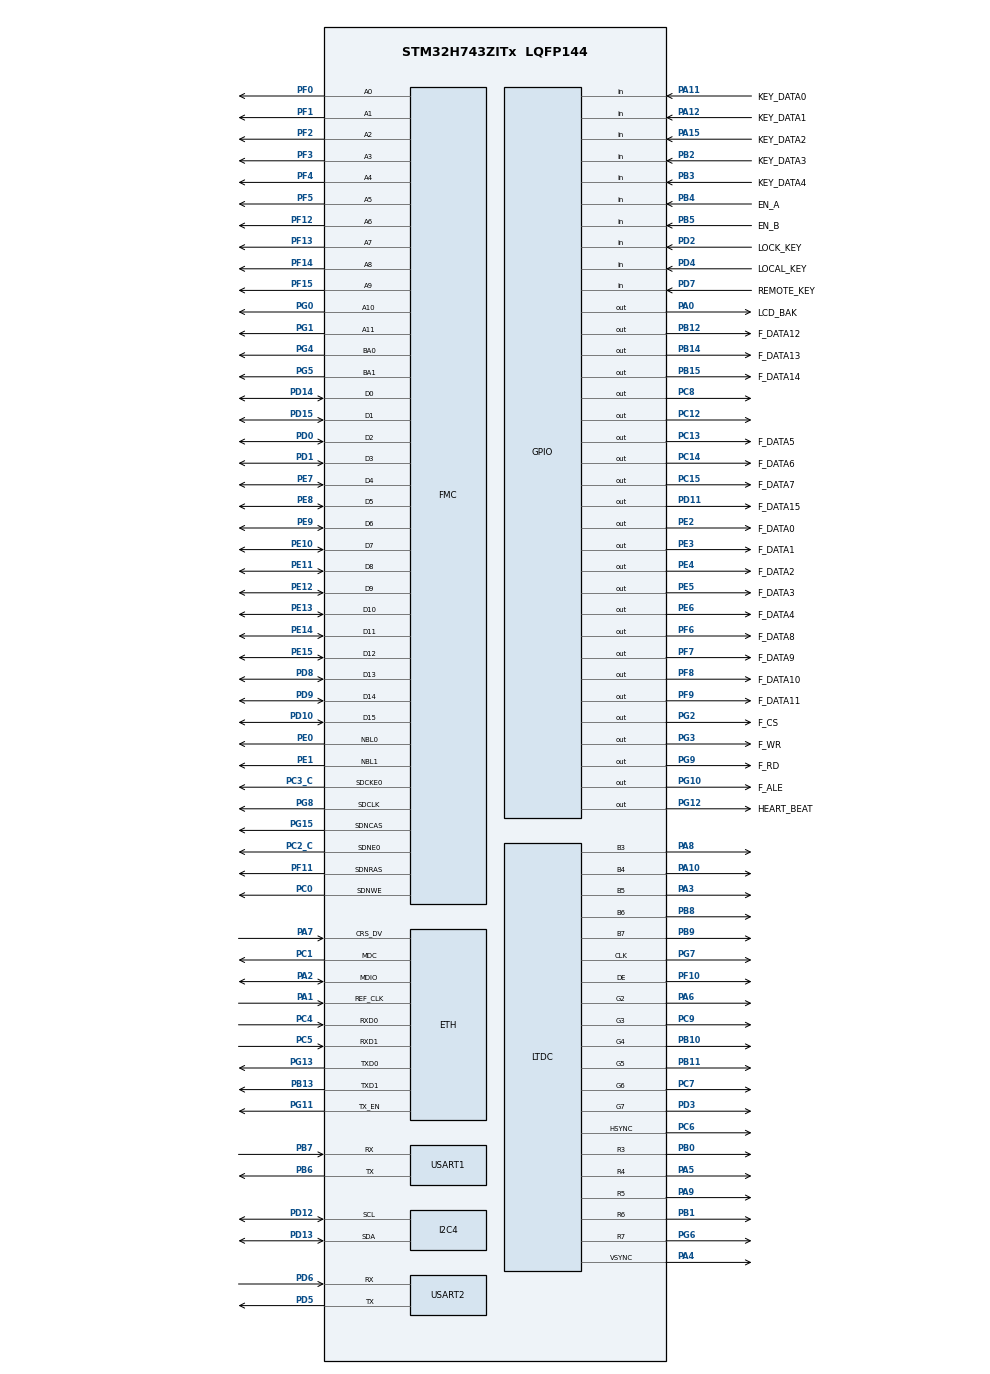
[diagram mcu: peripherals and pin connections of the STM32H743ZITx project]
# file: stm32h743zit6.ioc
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CORTEX_M7.AccessPermission_S-Cortex_Memory_Protection_Unit_Region1_Settings_S=MPU_REGION_FULL_ACCESS
CORTEX_M7.AccessPermission_S-Cortex_Memory_Protection_Unit_Region2_Settings_S=MPU_REGION_FULL_ACCESS
CORTEX_M7.AccessPermission_S-Cortex_Memory_Protection_Unit_Region3_Settings_S=MPU_REGION_FULL_ACCESS
CORTEX_M7.BaseAddress_S-Cortex_Memory_Protection_Unit_Region1_Settings_S=0x30020000
CORTEX_M7.BaseAddress_S-Cortex_Memory_Protection_Unit_Region2_Settings_S=0x30040000
CORTEX_M7.BaseAddress_S-Cortex_Memory_Protection_Unit_Region3_Settings_S=0xC0000000
CORTEX_M7.CPU_DCache=Enabled
CORTEX_M7.CPU_ICache=Enabled
CORTEX_M7.DisableExec_S-Cortex_Memory_Protection_Unit_Region1_Settings_S=MPU_INSTRUCTION_ACCESS_DISABLE
CORTEX_M7.DisableExec_S-Cortex_Memory_Protection_Unit_Region2_Settings_S=MPU_INSTRUCTION_ACCESS_DISABLE
CORTEX_M7.DisableExec_S-Cortex_Memory_Protection_Unit_Region3_Settings_S=MPU_INSTRUCTION_ACCESS_DISABLE
CORTEX_M7.Enable_S-Cortex_Memory_Protection_Unit_Region1_Settings_S=MPU_REGION_ENABLE
CORTEX_M7.Enable_S-Cortex_Memory_Protection_Unit_Region2_Settings_S=MPU_REGION_ENABLE
CORTEX_M7.Enable_S-Cortex_Memory_Protection_Unit_Region3_Settings_S=MPU_REGION_ENABLE
CORTEX_M7.Enable_S-Cortex_Memory_Protection_Unit_Region4_Settings_S=__NULL
CORTEX_M7.Enable_S-Cortex_Memory_Protection_Unit_Region5_Settings_S=__NULL
CORTEX_M7.IsBufferable_S-Cortex_Memory_Protection_Unit_Region2_Settings_S=MPU_ACCESS_BUFFERABLE
CORTEX_M7.IsBufferable_S-Cortex_Memory_Protection_Unit_Region3_Settings_S=MPU_ACCESS_NOT_BUFFERABLE
CORTEX_M7.IsCacheable_S-Cortex_Memory_Protection_Unit_Region3_Settings_S=MPU_ACCESS_NOT_CACHEABLE
CORTEX_M7.IsShareable_S-Cortex_Memory_Protection_Unit_Region2_Settings_S=MPU_ACCESS_SHAREABLE
CORTEX_M7.IsShareable_S-Cortex_Memory_Protection_Unit_Region3_Settings_S=MPU_ACCESS_NOT_SHAREABLE
CORTEX_M7.MPU_Control=MPU_PRIVILEGED_DEFAULT
CORTEX_M7.Size_S-Cortex_Memory_Protection_Unit_Region1_Settings_S=MPU_REGION_SIZE_128KB
CORTEX_M7.Size_S-Cortex_Memory_Protection_Unit_Region2_Settings_S=MPU_REGION_SIZE_512B
CORTEX_M7.Size_S-Cortex_Memory_Protection_Unit_Region3_Settings_S=MPU_REGION_SIZE_8MB
CORTEX_M7.TypeExtField_S-Cortex_Memory_Protection_Unit_Region1_Settings_S=MPU_TEX_LEVEL1
CORTEX_M7.default_mode_Activation=1
DMA2D.ColorMode=DMA2D_OUTPUT_RGB565
ETH.ETH_RX_DESC_CNT=4
ETH.ETH_TX_DESC_CNT=4
ETH.MediaInterface=HAL_ETH_RMII_MODE
ETH.RxDescAddress=0x30040000
ETH.TxDescAddress=0x30040200
FMC.CASLatency1=FMC_SDRAM_CAS_LATENCY_2
FMC.ColumnBitsNumber1=FMC_SDRAM_COLUMN_BITS_NUM_8
FMC.ExitSelfRefreshDelay1=7
FMC.LoadToActiveDelay1=2
FMC.RCDDelay1=2
FMC.RPDelay1=2
FMC.ReadBurst1=FMC_SDRAM_RBURST_ENABLE
FMC.ReadPipeDelay1=FMC_SDRAM_RPIPE_DELAY_1
FMC.ReadPipeDelay2=FMC_SDRAM_RPIPE_DELAY_1
FMC.RowCycleDelay1=7
FMC.RowCycleDelay2=7
FMC.SDClockPeriod1=FMC_SDRAM_CLOCK_PERIOD_2
FMC.SelfRefreshTime1=4
FMC.WriteRecoveryTime1=3
FREERTOS.Tasks01=MainTask,0,256,StartDefaultTask,Default,NULL,Dynamic,NULL,NULL
I2C4.Timing=0x307075B1
LTDC.ActiveH=272
LTDC.ActiveW=480
LTDC.Alpha0_L0=255
LTDC.Alpha0_L1=255
LTDC.Alpha_L0=255
LTDC.Alpha_L1=255
LTDC.DEPolarity=LTDC_DEPOLARITY_AH
LTDC.FBStartAdress_L0=0xC0000000
LTDC.FBStartAdress_L1=0xC0000000
LTDC.HBP=43
LTDC.HFP=8
LTDC.HSync=4
LTDC.ImageHeight_L0=272
LTDC.ImageHeight_L1=272
LTDC.ImageWidth_L0=480
LTDC.Layers=0
LTDC.PCPolarity=LTDC_PCPOLARITY_IIPC
LTDC.PixelFormat_L0=LTDC_PIXEL_FORMAT_RGB565
LTDC.VBP=12
LTDC.VFP=8
LTDC.VSync=4
LTDC.WindowX1_L0=480
LTDC.WindowX1_L1=480
LTDC.WindowY1_L0=272
LTDC.WindowY1_L1=272
LWIP.BSP.number=1
LWIP.CHECKSUM_CHECK_ICMP=1
LWIP.CHECKSUM_GEN_ICMP=1
LWIP.DEFAULT_THREAD_STACKSIZE=2048
LWIP.ETH_RX_BUFFER_CNT=12
LWIP.GATEWAY_ADDRESS=192.168.000.000
LWIP.IP_ADDRESS=192.168.000.050
LWIP.LWIP_DHCP=0
LWIP.LWIP_RAM_HEAP_POINTER=0x30020000
LWIP.MEM_SIZE=131048
LWIP.NETMASK_ADDRESS=255.255.255.000
LWIP.SYS_LIGHTWEIGHT_PROT=1
LWIP.TCPIP_THREAD_STACKSIZE=2048
LWIP.TCP_MSS=1460
LWIP.TCP_QUEUE_OOSEQ=1
LWIP.TCP_SND_BUF=5840
LWIP.TCP_SND_QUEUELEN=16
LWIP.TCP_WND=5840
LWIP.Version=v2.1.2_Cube
LWIP0.BSP.STBoard=false
LWIP0.BSP.api=BSP_COMPONENT_DRIVER
LWIP0.BSP.component=LAN8742
LWIP0.BSP.instance=LAN8742
LWIP0.BSP.name=Driver_PHY
LWIP0.BSP.semaphore=S_LAN8742
LWIP0.BSP.solution=LAN8742
Mcu.Family=STM32H7
Mcu.Name=STM32H743ZITx
Mcu.Package=LQFP144
NVIC.ETH_IRQn=true\:5\:0\:false\:false\:true\:true\:true\:true\:true
NVIC.LTDC_ER_IRQn=true\:5\:0\:false\:false\:true\:true\:true\:true\:true
NVIC.LTDC_IRQn=true\:5\:0\:false\:false\:true\:true\:true\:true\:true
NVIC.PriorityGroup=NVIC_PRIORITYGROUP_4
NVIC.TIM1_UP_IRQn=true\:15\:0\:false\:false\:true\:false\:false\:true\:true
NVIC.TimeBase=TIM1_UP_IRQn
NVIC.TimeBaseIP=TIM1
PA0.GPIO_Label=LCD_BAK
PA0.Signal=GPIO_Output
PA1.GPIO_Speed=GPIO_SPEED_FREQ_VERY_HIGH
PA1.Mode=RMII
PA1.Signal=ETH_REF_CLK
PA10.GPIO_Speed=GPIO_SPEED_FREQ_VERY_HIGH
PA10.Mode=RGB565
PA10.Signal=LTDC_B4
PA11.GPIO_Label=KEY_DATA0
PA11.Signal=GPIO_Input
PA12.GPIO_Label=KEY_DATA1
PA12.Signal=GPIO_Input
PA13\ (JTMS/SWDIO).Mode=Serial_Wire
PA13\ (JTMS/SWDIO).Signal=DEBUG_JTMS-SWDIO
PA14\ (JTCK/SWCLK).Mode=Serial_Wire
PA14\ (JTCK/SWCLK).Signal=DEBUG_JTCK-SWCLK
PA15\ (JTDI).GPIO_Label=KEY_DATA2
PA15\ (JTDI).Signal=GPIO_Input
PA2.GPIO_Speed=GPIO_SPEED_FREQ_VERY_HIGH
PA2.Mode=RMII
PA2.Signal=ETH_MDIO
PA3.GPIO_Speed=GPIO_SPEED_FREQ_VERY_HIGH
PA3.Mode=RGB565
PA3.Signal=LTDC_B5
PA4.GPIO_Speed=GPIO_SPEED_FREQ_VERY_HIGH
PA4.Mode=RGB565
PA4.Signal=LTDC_VSYNC
PA5.GPIO_Speed=GPIO_SPEED_FREQ_VERY_HIGH
PA5.Mode=RGB565
PA5.Signal=LTDC_R4
PA6.GPIO_Speed=GPIO_SPEED_FREQ_VERY_HIGH
PA6.Mode=RGB565
PA6.Signal=LTDC_G2
PA7.GPIO_Speed=GPIO_SPEED_FREQ_VERY_HIGH
PA7.Mode=RMII
PA7.Signal=ETH_CRS_DV
PA8.GPIO_Speed=GPIO_SPEED_FREQ_VERY_HIGH
PA8.Mode=RGB565
PA8.Signal=LTDC_B3
PA9.GPIO_Speed=GPIO_SPEED_FREQ_VERY_HIGH
PA9.Mode=RGB565
PA9.Signal=LTDC_R5
PB0.GPIO_Speed=GPIO_SPEED_FREQ_VERY_HIGH
PB0.Mode=RGB565
PB0.Signal=LTDC_R3
PB1.GPIO_Speed=GPIO_SPEED_FREQ_VERY_HIGH
PB1.Mode=RGB565
PB1.Signal=LTDC_R6
PB10.GPIO_Speed=GPIO_SPEED_FREQ_VERY_HIGH
PB10.Mode=RGB565
PB10.Signal=LTDC_G4
PB11.GPIO_Speed=GPIO_SPEED_FREQ_VERY_HIGH
PB11.Mode=RGB565
PB11.Signal=LTDC_G5
PB12.GPIO_Label=F_DATA12
PB12.Signal=GPIO_Output
PB13.GPIO_Speed=GPIO_SPEED_FREQ_VERY_HIGH
PB13.Mode=RMII
PB13.Signal=ETH_TXD1
PB14.GPIO_Label=F_DATA13
PB14.Signal=GPIO_Output
PB15.GPIO_Label=F_DATA14
PB15.Signal=GPIO_Output
PB2.GPIO_Label=KEY_DATA3
PB2.Signal=GPIO_Input
PB3\ (JTDO/TRACESWO).GPIO_Label=KEY_DATA4
PB3\ (JTDO/TRACESWO).Signal=GPIO_Input
PB4\ (NJTRST).GPIO_Label=EN_A
PB4\ (NJTRST).Signal=GPIO_Input
PB5.GPIO_Label=EN_B
PB5.Signal=GPIO_Input
PB6.Mode=Asynchronous
PB6.Signal=USART1_TX
PB7.Mode=Asynchronous
PB7.Signal=USART1_RX
PB8.GPIO_FM8=SYSCFG_PMCR_I2C_PB8_FMP
PB8.GPIO_Speed=GPIO_SPEED_FREQ_VERY_HIGH
PB8.Mode=RGB565
PB8.Signal=LTDC_B6
PB9.GPIO_FM9=SYSCFG_PMCR_I2C_PB9_FMP
PB9.GPIO_Speed=GPIO_SPEED_FREQ_VERY_HIGH
PB9.Mode=RGB565
PB9.Signal=LTDC_B7
PC0.Signal=FMC_SDNWE
PC1.GPIO_Speed=GPIO_SPEED_FREQ_VERY_HIGH
PC1.Mode=RMII
PC1.Signal=ETH_MDC
PC12.Signal=GPIO_Output
PC13.GPIO_Label=F_DATA5
PC13.Signal=GPIO_Output
PC14-OSC32_IN\ (OSC32_IN).GPIO_Label=F_DATA6
PC14-OSC32_IN\ (OSC32_IN).Signal=GPIO_Output
PC15-OSC32_OUT\ (OSC32_OUT).GPIO_Label=F_DATA7
PC15-OSC32_OUT\ (OSC32_OUT).Signal=GPIO_Output
PC2_C.Mode=SdramChipSelect1_1
PC2_C.Signal=FMC_SDNE0
PC3_C.Mode=SdramChipSelect1_1
PC3_C.PinAttribute=Free
PC3_C.Signal=FMC_SDCKE0
PC4.GPIO_Speed=GPIO_SPEED_FREQ_VERY_HIGH
PC4.Mode=RMII
PC4.Signal=ETH_RXD0
PC5.GPIO_Speed=GPIO_SPEED_FREQ_VERY_HIGH
PC5.Mode=RMII
PC5.Signal=ETH_RXD1
PC6.GPIO_Speed=GPIO_SPEED_FREQ_VERY_HIGH
PC6.Mode=RGB565
PC6.Signal=LTDC_HSYNC
PC7.GPIO_Speed=GPIO_SPEED_FREQ_VERY_HIGH
PC7.Mode=RGB565
PC7.Signal=LTDC_G6
PC8.Signal=GPIO_Output
PC9.GPIO_Speed=GPIO_SPEED_FREQ_VERY_HIGH
PC9.Mode=RGB565
PC9.Signal=LTDC_G3
PD0.Signal=FMC_D2_DA2
PD1.Signal=FMC_D3_DA3
PD10.Signal=FMC_D15_DA15
PD11.GPIO_Label=F_DATA15
PD11.Signal=GPIO_Output
PD12.Mode=I2C
PD12.Signal=I2C4_SCL
PD13.Mode=I2C
PD13.Signal=I2C4_SDA
PD14.Signal=FMC_D0_DA0
PD15.Signal=FMC_D1_DA1
PD2.GPIO_Label=LOCK_KEY
PD2.Signal=GPIO_Input
PD3.GPIO_Speed=GPIO_SPEED_FREQ_VERY_HIGH
PD3.Mode=RGB565
PD3.Signal=LTDC_G7
PD4.GPIO_Label=LOCAL_KEY
PD4.Signal=GPIO_Input
PD5.Mode=Asynchronous
PD5.Signal=USART2_TX
PD6.Mode=Asynchronous
PD6.Signal=USART2_RX
PD7.GPIO_Label=REMOTE_KEY
PD7.Signal=GPIO_Input
PD8.Signal=FMC_D13_DA13
PD9.Signal=FMC_D14_DA14
PE0.Signal=FMC_NBL0
PE1.Signal=FMC_NBL1
PE10.Signal=FMC_D7_DA7
PE11.Signal=FMC_D8_DA8
PE12.Signal=FMC_D9_DA9
PE13.Signal=FMC_D10_DA10
PE14.Signal=FMC_D11_DA11
PE15.Signal=FMC_D12_DA12
PE2.GPIO_Label=F_DATA0
PE2.Signal=GPIO_Output
PE3.GPIO_Label=F_DATA1
PE3.Signal=GPIO_Output
PE4.GPIO_Label=F_DATA2
PE4.Signal=GPIO_Output
PE5.GPIO_Label=F_DATA3
PE5.Signal=GPIO_Output
PE6.GPIO_Label=F_DATA4
PE6.Signal=GPIO_Output
PE7.Signal=FMC_D4_DA4
PE8.Signal=FMC_D5_DA5
PE9.Signal=FMC_D6_DA6
PF0.Signal=FMC_A0
PF1.Signal=FMC_A1
PF10.GPIO_Speed=GPIO_SPEED_FREQ_VERY_HIGH
PF10.Mode=RGB565
PF10.Signal=LTDC_DE
PF11.Signal=FMC_SDNRAS
PF12.Signal=FMC_A6
PF13.Signal=FMC_A7
PF14.Signal=FMC_A8
PF15.Signal=FMC_A9
PF2.Signal=FMC_A2
PF3.Signal=FMC_A3
PF4.Signal=FMC_A4
PF5.Signal=FMC_A5
PF6.GPIO_Label=F_DATA8
PF6.Signal=GPIO_Output
PF7.GPIO_Label=F_DATA9
PF7.Signal=GPIO_Output
PF8.GPIO_Label=F_DATA10
PF8.Signal=GPIO_Output
PF9.GPIO_Label=F_DATA11
PF9.Signal=GPIO_Output
PG0.Signal=FMC_A10
PG1.Signal=FMC_A11
PG10.GPIO_Label=F_ALE
PG10.Signal=GPIO_Output
PG11.GPIO_Speed=GPIO_SPEED_FREQ_VERY_HIGH
PG11.Mode=RMII
PG11.Signal=ETH_TX_EN
PG12.GPIO_Label=HEART_BEAT
PG12.Signal=GPIO_Output
PG13.GPIO_Speed=GPIO_SPEED_FREQ_VERY_HIGH
PG13.Mode=RMII
PG13.Signal=ETH_TXD0
PG15.Signal=FMC_SDNCAS
PG2.GPIO_Label=F_CS
PG2.Signal=GPIO_Output
PG3.GPIO_Label=F_WR
PG3.Signal=GPIO_Output
PG4.Signal=FMC_A14_BA0
PG5.Signal=FMC_A15_BA1
PG6.GPIO_Speed=GPIO_SPEED_FREQ_VERY_HIGH
PG6.Mode=RGB565
PG6.Signal=LTDC_R7
PG7.GPIO_Speed=GPIO_SPEED_FREQ_VERY_HIGH
PG7.Mode=RGB565
PG7.Signal=LTDC_CLK
PG8.Signal=FMC_SDCLK
PG9.GPIO_Label=F_RD
PG9.Signal=GPIO_Output
PH0-OSC_IN\ (PH0).Mode=HSE-External-Oscillator
PH0-OSC_IN\ (PH0).Signal=RCC_OSC_IN
PH1-OSC_OUT\ (PH1).Mode=HSE-External-Oscillator
PH1-OSC_OUT\ (PH1).Signal=RCC_OSC_OUT
ProjectManager.HeapSize=0x200
ProjectManager.StackSize=0x400
ProjectManager.TargetToolchain=STM32CubeIDE
RCC.ADCFreq_Value=143750000
RCC.APB1Freq_Value=120000000
RCC.APB2Freq_Value=120000000
RCC.APB3Freq_Value=120000000
RCC.APB4Freq_Value=120000000
RCC.CortexFreq_Value=480000000
RCC.D1PPRE=RCC_APB3_DIV2
RCC.D2PPRE1=RCC_APB1_DIV2
RCC.D2PPRE2=RCC_APB2_DIV2
RCC.D3PPRE=RCC_APB4_DIV2
RCC.DIVM1=5
RCC.DIVM2=6
RCC.DIVM3=16
RCC.DIVN1=192
RCC.DIVN2=69
RCC.DIVN3=140
RCC.DIVQ2=4
RCC.DIVR3=36
RCC.FMCCLockSelection=RCC_FMCCLKSOURCE_PLL2
RCC.HCLKFreq_Value=240000000
RCC.HPRE=RCC_HCLK_DIV2
RCC.PLL2FRACN=0
RCC.PLL3FRACN=0
RCC.PLLFRACN=0
RCC.PLLSourceVirtual=RCC_PLLSOURCE_HSE
RCC.SYSCLKFreq_VALUE=480000000
RCC.SYSCLKSource=RCC_SYSCLKSOURCE_PLLCLK
RCC.USBFreq_Value=480000000
SH.FMC_A0.0=FMC_A0,12b-sda1
SH.FMC_A1.0=FMC_A1,12b-sda1
SH.FMC_A10.0=FMC_A10,12b-sda1
SH.FMC_A11.0=FMC_A11,12b-sda1
SH.FMC_A14_BA0.0=FMC_BA0,FourSdramBanks1
SH.FMC_A15_BA1.0=FMC_BA1,FourSdramBanks1
SH.FMC_A2.0=FMC_A2,12b-sda1
SH.FMC_A3.0=FMC_A3,12b-sda1
SH.FMC_A4.0=FMC_A4,12b-sda1
SH.FMC_A5.0=FMC_A5,12b-sda1
SH.FMC_A6.0=FMC_A6,12b-sda1
SH.FMC_A7.0=FMC_A7,12b-sda1
SH.FMC_A8.0=FMC_A8,12b-sda1
SH.FMC_A9.0=FMC_A9,12b-sda1
SH.FMC_D0_DA0.0=FMC_D0,sd-16b-d1
SH.FMC_D10_DA10.0=FMC_D10,sd-16b-d1
SH.FMC_D11_DA11.0=FMC_D11,sd-16b-d1
SH.FMC_D12_DA12.0=FMC_D12,sd-16b-d1
SH.FMC_D13_DA13.0=FMC_D13,sd-16b-d1
SH.FMC_D14_DA14.0=FMC_D14,sd-16b-d1
SH.FMC_D15_DA15.0=FMC_D15,sd-16b-d1
SH.FMC_D1_DA1.0=FMC_D1,sd-16b-d1
SH.FMC_D2_DA2.0=FMC_D2,sd-16b-d1
SH.FMC_D3_DA3.0=FMC_D3,sd-16b-d1
SH.FMC_D4_DA4.0=FMC_D4,sd-16b-d1
SH.FMC_D5_DA5.0=FMC_D5,sd-16b-d1
SH.FMC_D6_DA6.0=FMC_D6,sd-16b-d1
SH.FMC_D7_DA7.0=FMC_D7,sd-16b-d1
SH.FMC_D8_DA8.0=FMC_D8,sd-16b-d1
SH.FMC_D9_DA9.0=FMC_D9,sd-16b-d1
SH.FMC_NBL0.0=FMC_NBL0,Sd2ByteEnable1
SH.FMC_NBL1.0=FMC_NBL1,Sd2ByteEnable1
SH.FMC_SDCLK.0=FMC_SDCLK,12b-sda1
SH.FMC_SDNCAS.0=FMC_SDNCAS,12b-sda1
SH.FMC_SDNRAS.0=FMC_SDNRAS,12b-sda1
SH.FMC_SDNWE.0=FMC_SDNWE,12b-sda1
USART1.VirtualMode-Asynchronous=VM_ASYNC
USART2.VirtualMode-Asynchronous=VM_ASYNC
VP_DMA2D_VS_DMA2D.Mode=DMA2D_Activate
VP_FREERTOS_VS_CMSIS_V1.Mode=CMSIS_V1
VP_LWIP_VS_Enabled.Mode=Enabled
VP_MEMORYMAP_VS_MEMORYMAP.Mode=CurAppReg
VP_SYS_VS_tim1.Mode=TIM1
board=custom

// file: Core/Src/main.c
/* USER CODE BEGIN Header */
/**
  ******************************************************************************
  * @file           : main.c
  * @brief          : Main program body
  ******************************************************************************
  * @attention
  *
  * Copyright (c) 2026 STMicroelectronics.
  * All rights reserved.
  *
  * This software is licensed under terms that can be found in the LICENSE file
  * in the root directory of this software component.
  * If no LICENSE file comes with this software, it is provided AS-IS.
  *
  ******************************************************************************
  */
/* USER CODE END Header */
#include "main.h"
#include "cmsis_os.h"
#include "lwip.h"

/* USER CODE BEGIN Includes */
#include <stdint.h>
#include <string.h>
#include <stdbool.h>
#include "stm32h743xx.h"
#include "stm32h7xx_hal_cortex.h"
#include "tcp_ip.h"
#include "lwip/tcp.h"
#include "lwip/pbuf.h"
#include "lcd.h"
#include "../Middlewares/lvgl/lvgl.h"
#include "lv_port_disp.h"
#include "lv_port_indev.h"
#include "com_define.h"
#include "sdram.h"
#include "widgets.h"
#include "hw.h"
#include <stdio.h>
#include <sys/types.h>
#include "user_def.h"
#include "ax_uart2.h"
#include "packet_task.h"
#include "ax_mcu_if.h"
#include "ax_eeprom.h"
#include "reg_addr.h"
#include "ax_eeprom_task.h"
#include "com_widget.h"
/* USER CODE END Includes */

/* USER CODE BEGIN PTD */
uint16_t *FrameBuffer = (uint16_t *)LCD_FB_ADDR;
extern struct netif gnetif;
/* USER CODE END PTD */

DMA2D_HandleTypeDef hdma2d;

I2C_HandleTypeDef hi2c4;

LTDC_HandleTypeDef hltdc;

UART_HandleTypeDef huart1;
UART_HandleTypeDef huart2;

SDRAM_HandleTypeDef hsdram1;

osThreadId MainTaskHandle;
/* USER CODE BEGIN PV */

static void MX_NVIC_Init(void);
void HAL_UART_RxCpltCallback(UART_HandleTypeDef *huart);
/* USER CODE END PV */

void SystemClock_Config(void);
static void MPU_Config(void);
static void MX_GPIO_Init(void);
static void MX_FMC_Init(void);
static void MX_I2C4_Init(void);
static void MX_USART1_UART_Init(void);
static void MX_USART2_UART_Init(void);
static void MX_DMA2D_Init(void);
static void MX_LTDC_Init(void);
void StartDefaultTask(void const * argument);

/* USER CODE BEGIN PFP */
uint8_t gete_way_ip[4] = {192,168,0,1};	//user set up
uint8_t user_ip[4] = {192,168,0,50};
uint16_t Port_No = 5001;
uint32_t g_rs232_baud = 115200;

volatile bool btcp_connect = false;

#define U2_RX_BUF_SZ 256  //uart 버퍼 크기
volatile uint8_t u2_rx_buf[U2_RX_BUF_SZ];
volatile uint16_t u2_rx_w = 0;
uint8_t rx2_data = 0;

uint8_t g_tcp_recv_buffer[TCP_RECV_BUF_SIZE];	//TCP로 데이터를 받는다...
volatile uint32_t g_tcp_recv_len = 0;
volatile bool g_tcp_new_data_flag = false;
/* USER CODE END PFP */

int main(void)
{

  /* MPU Configuration--------------------------------------------------------*/
  MPU_Config();

  /* Enable the CPU Cache */

  /* Enable I-Cache---------------------------------------------------------*/
  SCB_EnableICache();

  /* Enable D-Cache---------------------------------------------------------*/
  SCB_EnableDCache();

  /* MCU Configuration--------------------------------------------------------*/

  /* Reset of all peripherals, Initializes the Flash interface and the Systick. */
  HAL_Init();

  /* Configure the system clock */
  SystemClock_Config();

  /* Initialize all configured peripherals */
  MX_GPIO_Init();
  MX_FMC_Init();
  MX_I2C4_Init();
  MX_USART1_UART_Init();
  MX_USART2_UART_Init();
  MX_DMA2D_Init();
  MX_LTDC_Init();
  /* USER CODE BEGIN 2 */
  MX_NVIC_Init();

  //LAN8742 RESET PIN
  HAL_GPIO_WritePin(GPIOC, GPIO_PIN_10, GPIO_PIN_RESET);
  HAL_Delay(100);
  HAL_GPIO_WritePin(GPIOC, GPIO_PIN_10, GPIO_PIN_SET);
  HAL_Delay(500);

  HAL_GPIO_WritePin(GPIOC, GPIO_PIN_8, GPIO_PIN_SET);	//DISP Control
  HAL_Delay(250); // Datasheet: Wait T2 (250ms min) after DISP High before turning on Backlight
  HAL_GPIO_WritePin(GPIOA, LCD_BAK_Pin, GPIO_PIN_RESET);	//LCD Backlight off

  packet_init();
  HAL_Delay(1000);

  setvbuf(stdout, NULL, _IONBF, 0); // No buffering

  HAL_StatusTypeDef st = HAL_UART_Receive_IT(&huart2, &rx2_data, 1);
  if(st != HAL_OK) {
    uart2_puts("\r\nUSART2 Receive_IT failed\r\n");
  }

  printf("\r\n\r\n App Start 2025. 12. 10b \r\n");
  uart2_puts("\r\n\r\n [Debug] App Start 2025. 12. 10b \r\n");

//  HAL_UART_Receive_IT(&huart1, (uint8_t*) &rx1_data, 1);
//  HAL_UART_Receive_IT(&huart2, (uint8_t*) &rx2_data, 1);
  HAL_Delay(100);

  // -----------------------------------------------------------------------------
  // power on, eeprom 에서 데이터를 읽어옴.
  // g_oper_mode =  0; //트리거모드
  // g_oper_mode =  1; //시퀀스모드
  // default_value_init(); //기본 값
  // eeprom_save_sys();

//  eeprom_save_facotry();

  eeprom_load_sys();					// load sys data from eeprom
  load_user_param(g_user_default);		// load trig_mode param from eeprom
  eeprom_load_page_all();				// load sequence mode param from eeprom

  mcu_write16(rSTROBE_EN, 0xffff);		// fpga write, strobe_enable
  mcu_write16(rSTROBE_EN, 0xffff);
  uart2_puts_16h("\r\n rSTROBE_EN : 0x", mcu_read16(rSTROBE_EN));

  /* USER CODE END 2 */

  /* Create the thread(s) */
  /* definition and creation of MainTask */
  osThreadDef(MainTask, StartDefaultTask, osPriorityNormal, 0, 2048);
  MainTaskHandle = osThreadCreate(osThread(MainTask), NULL);

  /* Start scheduler */
  osKernelStart();

  /* We should never get here as control is now taken by the scheduler */

  /* Infinite loop */
  while (1)
  {

  }
}

void SystemClock_Config(void)
{
  RCC_OscInitTypeDef RCC_OscInitStruct = {0};
  RCC_ClkInitTypeDef RCC_ClkInitStruct = {0};

  /** Supply configuration update enable
  */
  HAL_PWREx_ConfigSupply(PWR_LDO_SUPPLY);

  /** Configure the main internal regulator output voltage
  */
  __HAL_PWR_VOLTAGESCALING_CONFIG(PWR_REGULATOR_VOLTAGE_SCALE3);

  while(!__HAL_PWR_GET_FLAG(PWR_FLAG_VOSRDY)) {}

  /** Macro to configure the PLL clock source
  */
  __HAL_RCC_PLL_PLLSOURCE_CONFIG(RCC_PLLSOURCE_HSE);

  /** Initializes the RCC Oscillators according to the specified parameters
  * in the RCC_OscInitTypeDef structure.
  */
  RCC_OscInitStruct.OscillatorType = RCC_OSCILLATORTYPE_HSI|RCC_OSCILLATORTYPE_HSE;
  RCC_OscInitStruct.HSEState = RCC_HSE_ON;
  RCC_OscInitStruct.HSIState = RCC_HSI_DIV1;
  RCC_OscInitStruct.HSICalibrationValue = RCC_HSICALIBRATION_DEFAULT;
  RCC_OscInitStruct.PLL.PLLState = RCC_PLL_NONE;
  if (HAL_RCC_OscConfig(&RCC_OscInitStruct) != HAL_OK)
  {
    Error_Handler();
  }

  /** Initializes the CPU, AHB and APB buses clocks
  */
  RCC_ClkInitStruct.ClockType = RCC_CLOCKTYPE_HCLK|RCC_CLOCKTYPE_SYSCLK
                              |RCC_CLOCKTYPE_PCLK1|RCC_CLOCKTYPE_PCLK2
                              |RCC_CLOCKTYPE_D3PCLK1|RCC_CLOCKTYPE_D1PCLK1;
  RCC_ClkInitStruct.SYSCLKSource = RCC_SYSCLKSOURCE_HSI;
  RCC_ClkInitStruct.SYSCLKDivider = RCC_SYSCLK_DIV1;
  RCC_ClkInitStruct.AHBCLKDivider = RCC_HCLK_DIV1;
  RCC_ClkInitStruct.APB3CLKDivider = RCC_APB3_DIV1;
  RCC_ClkInitStruct.APB1CLKDivider = RCC_APB1_DIV2;
  RCC_ClkInitStruct.APB2CLKDivider = RCC_APB2_DIV2;
  RCC_ClkInitStruct.APB4CLKDivider = RCC_APB4_DIV2;

  if (HAL_RCC_ClockConfig(&RCC_ClkInitStruct, FLASH_LATENCY_1) != HAL_OK)
  {
    Error_Handler();
  }
}

static void MX_DMA2D_Init(void)
{

  hdma2d.Instance = DMA2D;
  hdma2d.Init.Mode = DMA2D_M2M;
  hdma2d.Init.ColorMode = DMA2D_OUTPUT_RGB565;
  hdma2d.Init.OutputOffset = 0;
  hdma2d.LayerCfg[1].InputOffset = 0;
  hdma2d.LayerCfg[1].InputColorMode = DMA2D_INPUT_RGB565;
  hdma2d.LayerCfg[1].AlphaMode = DMA2D_NO_MODIF_ALPHA;
  hdma2d.LayerCfg[1].InputAlpha = 0;
  hdma2d.LayerCfg[1].AlphaInverted = DMA2D_REGULAR_ALPHA;
  hdma2d.LayerCfg[1].RedBlueSwap = DMA2D_RB_REGULAR;
  hdma2d.LayerCfg[1].ChromaSubSampling = DMA2D_NO_CSS;
  if (HAL_DMA2D_Init(&hdma2d) != HAL_OK)
  {
    Error_Handler();
  }
  if (HAL_DMA2D_ConfigLayer(&hdma2d, 1) != HAL_OK)
  {
    Error_Handler();
  }

}

static void MX_NVIC_Init(void)
{
//   /* DMA2D_IRQn interrupt configuration */
//   HAL_NVIC_SetPriority(DMA2D_IRQn, 5, 0);
//   HAL_NVIC_EnableIRQ(DMA2D_IRQn);
  HAL_NVIC_SetPriority(USART2_IRQn, 6, 0);
  HAL_NVIC_EnableIRQ(USART2_IRQn);
}

void HAL_UART_RxCpltCallback(UART_HandleTypeDef *huart)
{
  if (huart->Instance == USART2)
  {
    u2_rx_buf[u2_rx_w++ % U2_RX_BUF_SZ] = rx2_data;

    // 다음 바이트 수신 재개
    HAL_UART_Receive_IT(&huart2, &rx2_data, 1);
  }
}

static void MX_I2C4_Init(void)
{

  hi2c4.Instance = I2C4;
  hi2c4.Init.Timing = 0x00707CBB;
  hi2c4.Init.OwnAddress1 = 0;
  hi2c4.Init.AddressingMode = I2C_ADDRESSINGMODE_7BIT;
  hi2c4.Init.DualAddressMode = I2C_DUALADDRESS_DISABLE;
  hi2c4.Init.OwnAddress2 = 0;
  hi2c4.Init.OwnAddress2Masks = I2C_OA2_NOMASK;
  hi2c4.Init.GeneralCallMode = I2C_GENERALCALL_DISABLE;
  hi2c4.Init.NoStretchMode = I2C_NOSTRETCH_DISABLE;
  if (HAL_I2C_Init(&hi2c4) != HAL_OK)
  {
    Error_Handler();
  }

  /** Configure Analogue filter
  */
  if (HAL_I2CEx_ConfigAnalogFilter(&hi2c4, I2C_ANALOGFILTER_ENABLE) != HAL_OK)
  {
    Error_Handler();
  }

  /** Configure Digital filter
  */
  if (HAL_I2CEx_ConfigDigitalFilter(&hi2c4, 0) != HAL_OK)
  {
    Error_Handler();
  }

}

static void MX_LTDC_Init(void)
{

  LTDC_LayerCfgTypeDef pLayerCfg = {0};

  hltdc.Instance = LTDC;
  hltdc.Init.HSPolarity = LTDC_HSPOLARITY_AL;
  hltdc.Init.VSPolarity = LTDC_VSPOLARITY_AL;
  hltdc.Init.DEPolarity = LTDC_DEPOLARITY_AH;
  hltdc.Init.PCPolarity = LTDC_PCPOLARITY_IIPC;
  hltdc.Init.HorizontalSync = 3;
  hltdc.Init.VerticalSync = 3;
  hltdc.Init.AccumulatedHBP = 46;
  hltdc.Init.AccumulatedVBP = 15;
  hltdc.Init.AccumulatedActiveW = 526;
  hltdc.Init.AccumulatedActiveH = 287;
  hltdc.Init.TotalWidth = 534;
  hltdc.Init.TotalHeigh = 295;
  hltdc.Init.Backcolor.Blue = 0;
  hltdc.Init.Backcolor.Green = 0;
  hltdc.Init.Backcolor.Red = 0;
  if (HAL_LTDC_Init(&hltdc) != HAL_OK)
  {
    Error_Handler();
  }
  pLayerCfg.WindowX0 = 0;
  pLayerCfg.WindowX1 = 480;
  pLayerCfg.WindowY0 = 0;
  pLayerCfg.WindowY1 = 272;
  pLayerCfg.PixelFormat = LTDC_PIXEL_FORMAT_RGB565;
  pLayerCfg.Alpha = 255;
  pLayerCfg.Alpha0 = 255;
  pLayerCfg.BlendingFactor1 = LTDC_BLENDING_FACTOR1_CA;
  pLayerCfg.BlendingFactor2 = LTDC_BLENDING_FACTOR2_CA;
  pLayerCfg.FBStartAdress = LCD_ST_ADDR;
  pLayerCfg.ImageWidth = 480;
  pLayerCfg.ImageHeight = 272;
  pLayerCfg.Backcolor.Blue = 0;
  pLayerCfg.Backcolor.Green = 0;
  pLayerCfg.Backcolor.Red = 0;
  if (HAL_LTDC_ConfigLayer(&hltdc, &pLayerCfg, 0) != HAL_OK)
  {
    Error_Handler();
  }

}

static void MX_USART1_UART_Init(void)
{

  huart1.Instance = USART1;
  huart1.Init.BaudRate = 115200;
  huart1.Init.WordLength = UART_WORDLENGTH_8B;
  huart1.Init.StopBits = UART_STOPBITS_1;
  huart1.Init.Parity = UART_PARITY_NONE;
  huart1.Init.Mode = UART_MODE_TX_RX;
  huart1.Init.HwFlowCtl = UART_HWCONTROL_NONE;
  huart1.Init.OverSampling = UART_OVERSAMPLING_16;
  huart1.Init.OneBitSampling = UART_ONE_BIT_SAMPLE_DISABLE;
  huart1.Init.ClockPrescaler = UART_PRESCALER_DIV1;
  huart1.AdvancedInit.AdvFeatureInit = UART_ADVFEATURE_NO_INIT;
  if (HAL_UART_Init(&huart1) != HAL_OK)
  {
    Error_Handler();
  }
  if (HAL_UARTEx_SetTxFifoThreshold(&huart1, UART_TXFIFO_THRESHOLD_1_8) != HAL_OK)
  {
    Error_Handler();
  }
  if (HAL_UARTEx_SetRxFifoThreshold(&huart1, UART_RXFIFO_THRESHOLD_1_8) != HAL_OK)
  {
    Error_Handler();
  }
  if (HAL_UARTEx_DisableFifoMode(&huart1) != HAL_OK)
  {
    Error_Handler();
  }

}

static void MX_USART2_UART_Init(void)
{

  huart2.Instance = USART2;
  huart2.Init.BaudRate = 115200;
  huart2.Init.WordLength = UART_WORDLENGTH_8B;
  huart2.Init.StopBits = UART_STOPBITS_1;
  huart2.Init.Parity = UART_PARITY_NONE;
  huart2.Init.Mode = UART_MODE_TX_RX;
  huart2.Init.HwFlowCtl = UART_HWCONTROL_NONE;
  huart2.Init.OverSampling = UART_OVERSAMPLING_16;
  huart2.Init.OneBitSampling = UART_ONE_BIT_SAMPLE_DISABLE;
  huart2.Init.ClockPrescaler = UART_PRESCALER_DIV1;
  huart2.AdvancedInit.AdvFeatureInit = UART_ADVFEATURE_NO_INIT;
  if (HAL_UART_Init(&huart2) != HAL_OK)
  {
    Error_Handler();
  }
  if (HAL_UARTEx_SetTxFifoThreshold(&huart2, UART_TXFIFO_THRESHOLD_1_8) != HAL_OK)
  {
    Error_Handler();
  }
  if (HAL_UARTEx_SetRxFifoThreshold(&huart2, UART_RXFIFO_THRESHOLD_1_8) != HAL_OK)
  {
    Error_Handler();
  }
  if (HAL_UARTEx_DisableFifoMode(&huart2) != HAL_OK)
  {
    Error_Handler();
  }

}

/* FMC initialization function */
static void MX_FMC_Init(void)
{

  FMC_SDRAM_TimingTypeDef SdramTiming = {0};

  /** Perform the SDRAM1 memory initialization sequence
  */
  hsdram1.Instance = FMC_SDRAM_DEVICE;
  /* hsdram1.Init */
  hsdram1.Init.SDBank = FMC_SDRAM_BANK1;
  hsdram1.Init.ColumnBitsNumber = FMC_SDRAM_COLUMN_BITS_NUM_8;
  hsdram1.Init.RowBitsNumber = FMC_SDRAM_ROW_BITS_NUM_12;
  hsdram1.Init.MemoryDataWidth = FMC_SDRAM_MEM_BUS_WIDTH_16;
  hsdram1.Init.InternalBankNumber = FMC_SDRAM_INTERN_BANKS_NUM_4;
  hsdram1.Init.CASLatency = FMC_SDRAM_CAS_LATENCY_2;
  hsdram1.Init.WriteProtection = FMC_SDRAM_WRITE_PROTECTION_DISABLE;
  hsdram1.Init.SDClockPeriod = FMC_SDRAM_CLOCK_PERIOD_2;
  hsdram1.Init.ReadBurst = FMC_SDRAM_RBURST_ENABLE;
  hsdram1.Init.ReadPipeDelay = FMC_SDRAM_RPIPE_DELAY_1;
  /* SdramTiming */
  SdramTiming.LoadToActiveDelay = 2;
  SdramTiming.ExitSelfRefreshDelay = 7;
  SdramTiming.SelfRefreshTime = 4;
  SdramTiming.RowCycleDelay = 7;
  SdramTiming.WriteRecoveryTime = 3;
  SdramTiming.RPDelay = 2;
  SdramTiming.RCDDelay = 2;

  if (HAL_SDRAM_Init(&hsdram1, &SdramTiming) != HAL_OK)
  {
    Error_Handler( );
  }

  /* USER CODE BEGIN FMC_Init 2 */
static FMC_SDRAM_CommandTypeDef Command;

  Command.CommandMode            = FMC_SDRAM_CMD_CLK_ENABLE;
  Command.CommandTarget          = FMC_SDRAM_CMD_TARGET_BANK1;
  Command.AutoRefreshNumber      = 1;
  Command.ModeRegisterDefinition = 0;

  if(HAL_SDRAM_SendCommand(&hsdram1, &Command, SDRAM_TIMEOUT) != HAL_OK)
  {
	 printf("[  ] sdram step 1 fail\n");
	 Error_Handler( );
  }

//  osDelay(1);
  HAL_Delay(1);

  Command.CommandMode            = FMC_SDRAM_CMD_PALL;
  Command.CommandTarget          = FMC_SDRAM_CMD_TARGET_BANK1;
  Command.AutoRefreshNumber      = 1;
  Command.ModeRegisterDefinition = 0;
  if(HAL_SDRAM_SendCommand(&hsdram1, &Command, SDRAM_TIMEOUT) != HAL_OK)
  {
	printf("[  ] sdram step 3 fail\n");
	Error_Handler( );
  }

  Command.CommandMode            = FMC_SDRAM_CMD_AUTOREFRESH_MODE;
  Command.CommandTarget          = FMC_SDRAM_CMD_TARGET_BANK1;
  Command.AutoRefreshNumber      = 8;
  Command.ModeRegisterDefinition = 0;
  if(HAL_SDRAM_SendCommand(&hsdram1, &Command, SDRAM_TIMEOUT) != HAL_OK)
  {
	printf("[  ] sdram step 4 fail\n");
    Error_Handler( );
  }

  uint32_t mode_reg = 0;

  mode_reg |= (2 << 0); // Burst Length = 4
  mode_reg |= (0 << 3); // Burst Type
                        //   0 : Sequential
                        //   1 : Interleaved
  mode_reg |= (2 << 4); // CAS Latency Mode
                        //   2 :
                        //   3 :
  mode_reg |= (0 << 7); // Operation Mode
  mode_reg |= (0 << 9); // Write Burst Mode
                        //   0 : Programmed Burst Length
                        //   1 : Single Location Access

  Command.CommandMode            = FMC_SDRAM_CMD_LOAD_MODE;
  Command.CommandTarget          = FMC_SDRAM_CMD_TARGET_BANK1;
  Command.AutoRefreshNumber      = 1;
  Command.ModeRegisterDefinition = mode_reg;
  if(HAL_SDRAM_SendCommand(&hsdram1, &Command, SDRAM_TIMEOUT) != HAL_OK)
  {
	printf("[  ] sdram step 5 fail\n");
	Error_Handler( );
  }
// Step 6: Set the refresh rate counter
//
// refresh rate = (COUNT + 1) * SDRAM clock freq (95Mhz)
//
// COUNT = (SDRAM refresh period/Number of rows) - 20
//       = (64ms / 8192) - 20
//       = 7.81us * 95 - 20 = 722
  uint32_t fmc_hz   = FMC_GetKernelClock_Hz();
  uint32_t sdclk_hz = fmc_hz / 2; // SDClockPeriod=2 이면 FMC_CLK/2

  uint32_t refresh_count = SDRAM_RefreshCount_IS42S16400J(sdclk_hz);
  refresh_count = (refresh_count * 130) / 100;

  printf("FMC=%lu Hz, SDCLK=%lu Hz, refresh=%lu\r\n", (unsigned long)fmc_hz, (unsigned long)sdclk_hz, (unsigned long)refresh_count);

  HAL_SDRAM_ProgramRefreshRate(&hsdram1, refresh_count);

  if (HAL_SDRAM_ProgramRefreshRate(&hsdram1, refresh_count) != HAL_OK)
  {
	  printf("[  ] sdram step 5 fail\n");
	  Error_Handler();
  }
  /* USER CODE END FMC_Init 2 */
}

static void MX_GPIO_Init(void)
{
  GPIO_InitTypeDef GPIO_InitStruct = {0};

  /* GPIO Ports Clock Enable */
  __HAL_RCC_GPIOE_CLK_ENABLE();
  __HAL_RCC_GPIOC_CLK_ENABLE();
  __HAL_RCC_GPIOF_CLK_ENABLE();
  __HAL_RCC_GPIOH_CLK_ENABLE();
  __HAL_RCC_GPIOA_CLK_ENABLE();
  __HAL_RCC_GPIOB_CLK_ENABLE();
  __HAL_RCC_GPIOG_CLK_ENABLE();
  __HAL_RCC_GPIOD_CLK_ENABLE();

  /*Configure GPIO pin Output Level */
  HAL_GPIO_WritePin(GPIOE, F_DATA0_Pin|F_DATA1_Pin|F_DATA2_Pin|F_DATA3_Pin
                          |F_DATA4_Pin, GPIO_PIN_RESET);

  /*Configure GPIO pin Output Level */
  HAL_GPIO_WritePin(GPIOC, F_DATA5_Pin|F_DATA6_Pin|F_DATA7_Pin|GPIO_PIN_8
                          |GPIO_PIN_12, GPIO_PIN_RESET);

  /*Configure GPIO pin Output Level */
  HAL_GPIO_WritePin(GPIOF, F_DATA8_Pin|F_DATA9_Pin|F_DATA10_Pin|F_DATA11_Pin, GPIO_PIN_RESET);

  /*Configure GPIO pin Output Level */
  HAL_GPIO_WritePin(LCD_BAK_GPIO_Port, LCD_BAK_Pin, GPIO_PIN_RESET);

  /*Configure GPIO pin Output Level */
  HAL_GPIO_WritePin(GPIOB, F_DATA12_Pin|F_DATA13_Pin|F_DATA14_Pin, GPIO_PIN_RESET);

  /*Configure GPIO pin Output Level */
  HAL_GPIO_WritePin(F_DATA15_GPIO_Port, F_DATA15_Pin, GPIO_PIN_RESET);

  /*Configure GPIO pin Output Level */
  HAL_GPIO_WritePin(GPIOG, F_CS_Pin|F_WR_Pin|F_RD_Pin|F_ALE_Pin
                          |HEART_BEAT_Pin, GPIO_PIN_RESET);

  /*Configure GPIO pins : F_DATA0_Pin F_DATA1_Pin F_DATA2_Pin F_DATA3_Pin
                           F_DATA4_Pin */
  GPIO_InitStruct.Pin = F_DATA0_Pin|F_DATA1_Pin|F_DATA2_Pin|F_DATA3_Pin
                          |F_DATA4_Pin;
  GPIO_InitStruct.Mode = GPIO_MODE_OUTPUT_PP;
  GPIO_InitStruct.Pull = GPIO_NOPULL;
  GPIO_InitStruct.Speed = GPIO_SPEED_FREQ_LOW;
  HAL_GPIO_Init(GPIOE, &GPIO_InitStruct);

  /*Configure GPIO pins : F_DATA5_Pin F_DATA6_Pin F_DATA7_Pin PC8
                           PC12 */
  GPIO_InitStruct.Pin = F_DATA5_Pin|F_DATA6_Pin|F_DATA7_Pin|GPIO_PIN_8
                          |GPIO_PIN_12;
  GPIO_InitStruct.Mode = GPIO_MODE_OUTPUT_PP;
  GPIO_InitStruct.Pull = GPIO_NOPULL;
  GPIO_InitStruct.Speed = GPIO_SPEED_FREQ_LOW;
  HAL_GPIO_Init(GPIOC, &GPIO_InitStruct);

  /*Configure GPIO pins : F_DATA8_Pin F_DATA9_Pin F_DATA10_Pin F_DATA11_Pin */
  GPIO_InitStruct.Pin = F_DATA8_Pin|F_DATA9_Pin|F_DATA10_Pin|F_DATA11_Pin;
  GPIO_InitStruct.Mode = GPIO_MODE_OUTPUT_PP;
  GPIO_InitStruct.Pull = GPIO_NOPULL;
  GPIO_InitStruct.Speed = GPIO_SPEED_FREQ_LOW;
  HAL_GPIO_Init(GPIOF, &GPIO_InitStruct);

  /*Configure GPIO pin : LCD_BAK_Pin */
  GPIO_InitStruct.Pin = LCD_BAK_Pin;
  GPIO_InitStruct.Mode = GPIO_MODE_OUTPUT_PP;
  GPIO_InitStruct.Pull = GPIO_NOPULL;
  GPIO_InitStruct.Speed = GPIO_SPEED_FREQ_LOW;
  HAL_GPIO_Init(LCD_BAK_GPIO_Port, &GPIO_InitStruct);

  /*Configure GPIO pins : KEY_DATA3_Pin KEY_DATA4_Pin EN_A_Pin EN_B_Pin */
  GPIO_InitStruct.Pin = KEY_DATA3_Pin|KEY_DATA4_Pin|EN_A_Pin|EN_B_Pin;
  GPIO_InitStruct.Mode = GPIO_MODE_INPUT;
  GPIO_InitStruct.Pull = GPIO_NOPULL;
  HAL_GPIO_Init(GPIOB, &GPIO_InitStruct);

  /*Configure GPIO pins : F_DATA12_Pin F_DATA13_Pin F_DATA14_Pin */
  GPIO_InitStruct.Pin = F_DATA12_Pin|F_DATA13_Pin|F_DATA14_Pin;
  GPIO_InitStruct.Mode = GPIO_MODE_OUTPUT_PP;
  GPIO_InitStruct.Pull = GPIO_NOPULL;
  GPIO_InitStruct.Speed = GPIO_SPEED_FREQ_LOW;
  HAL_GPIO_Init(GPIOB, &GPIO_InitStruct);

  /*Configure GPIO pin : F_DATA15_Pin */
  GPIO_InitStruct.Pin = F_DATA15_Pin;
  GPIO_InitStruct.Mode = GPIO_MODE_OUTPUT_PP;
  GPIO_InitStruct.Pull = GPIO_NOPULL;
  GPIO_InitStruct.Speed = GPIO_SPEED_FREQ_LOW;
  HAL_GPIO_Init(F_DATA15_GPIO_Port, &GPIO_InitStruct);

  /*Configure GPIO pins : F_CS_Pin F_WR_Pin F_RD_Pin F_ALE_Pin
                           HEART_BEAT_Pin */
  GPIO_InitStruct.Pin = F_CS_Pin|F_WR_Pin|F_RD_Pin|F_ALE_Pin
                          |HEART_BEAT_Pin;
  GPIO_InitStruct.Mode = GPIO_MODE_OUTPUT_PP;
  GPIO_InitStruct.Pull = GPIO_NOPULL;
  GPIO_InitStruct.Speed = GPIO_SPEED_FREQ_LOW;
  HAL_GPIO_Init(GPIOG, &GPIO_InitStruct);

  /*Configure GPIO pins : KEY_DATA0_Pin KEY_DATA1_Pin KEY_DATA2_Pin */
  GPIO_InitStruct.Pin = KEY_DATA0_Pin|KEY_DATA1_Pin|KEY_DATA2_Pin;
  GPIO_InitStruct.Mode = GPIO_MODE_INPUT;
  GPIO_InitStruct.Pull = GPIO_NOPULL;
  HAL_GPIO_Init(GPIOA, &GPIO_InitStruct);

  /*Configure GPIO pins : LOCK_KEY_Pin LOCAL_KEY_Pin REMOTE_KEY_Pin */
  GPIO_InitStruct.Pin = LOCK_KEY_Pin|LOCAL_KEY_Pin|REMOTE_KEY_Pin;
  GPIO_InitStruct.Mode = GPIO_MODE_INPUT;
  GPIO_InitStruct.Pull = GPIO_NOPULL;
  HAL_GPIO_Init(GPIOD, &GPIO_InitStruct);

  /*AnalogSwitch Config */
  HAL_SYSCFG_AnalogSwitchConfig(SYSCFG_SWITCH_PA0, SYSCFG_SWITCH_PA0_CLOSE);

}

/* USER CODE BEGIN 4 */
void HAL_UART_ErrorCallback(UART_HandleTypeDef *huart)
{
    if (huart->Instance == USART2)
    {
        uint32_t error_code = HAL_UART_GetError(huart);
        printf("UART2 Error: 0x%lX\r\n", error_code);

        // Clear the error flags
        __HAL_UART_CLEAR_FLAG(huart, UART_CLEAR_OREF | UART_CLEAR_NEF | UART_CLEAR_FEF);

        // Restart the reception
        HAL_UART_Receive_IT(&huart2, &rx2_data, 1);
    }
}

void HAL_UART_AbortCpltCallback(UART_HandleTypeDef *huart)
{
	if (huart->Instance == USART2)
	{
		printf("UART2 Abort Complete\r\n");
	}
}
/* USER CODE END 4 */

void StartDefaultTask(void const * argument)
{
  /* init code for LWIP */
  MX_LWIP_Init();
  /* USER CODE BEGIN 5 */
  hwInit();
  tcp_ip_config(&gnetif, user_ip, gete_way_ip);
  printf("Waiting for IP...\n");

  /* Wait until IP acquired */
  while (ip4_addr_isany_val(*netif_ip4_addr(&gnetif))) {
		osDelay(200);
  }
  printf("IP Ready: %s\n", ip4addr_ntoa(netif_ip4_addr(&gnetif)));

  osDelay(200);

  LOCK_TCPIP_CORE();
  btcp_connect = tcp_server_init(Port_No);
  UNLOCK_TCPIP_CORE();

  memset((void*)FrameBuffer, 0x00, LCD_WIDTH * LCD_HEIGHT * 2);
  SCB_CleanDCache_by_Addr((uint32_t*)FrameBuffer, LCD_WIDTH * LCD_HEIGHT * 2);

  LCD_ShowLogo();
  SCB_CleanDCache_by_Addr((uint32_t *)FrameBuffer, LCD_WIDTH * LCD_HEIGHT * 2); // 2 bytes per pixel
  // 로고 준비 끝났으면 백라이트 ON
  HAL_GPIO_WritePin(GPIOA, LCD_BAK_Pin, GPIO_PIN_SET);
  osDelay(2000);

  lv_init();	//lvgl init
  lv_port_disp_init();	//display init
  lv_port_indev_init();	//input device init

  ui_strobe_t *ui = widgets_create_strobe_screen();
  lv_scr_load(ui->scr);

  lv_indev_t * enc = lv_port_indev_get_encoder();
  widgets_bind_encoder(ui, enc);

  uint32_t pre_time;
  pre_time = HAL_GetTick();

  /* Infinite loop */
  for(;;)
  {
    if(HAL_GetTick() - pre_time >= 500)
    {
      pre_time = HAL_GetTick();
      HAL_GPIO_TogglePin(GPIOG, GPIO_PIN_12);

      uart2_puts("\r\n\r\n [Debug] App Start 2025. 12. 10b \r\n");

      if(g_tcp_new_data_flag)
      {
        printf("Received new data: %.*s\n", (int)g_tcp_recv_len, g_tcp_recv_buffer);
        g_tcp_new_data_flag = false;

        char *response = "Ok\n";
        tcp_send_data((uint8_t*)response, strlen(response));
      }
    }

    lv_tick_inc(2);
    lv_port_indev_poll_5ms();	//키 및 로터리 스캔
    lv_timer_handler();

    // osDelay(1);
  }
  /* USER CODE END 5 */
}

 /* MPU Configuration */

void MPU_Config(void)
{
  MPU_Region_InitTypeDef MPU_InitStruct = {0};

  /* Disables the MPU */
  HAL_MPU_Disable();

  /** Initializes and configures the Region and the memory to be protected
  */
  MPU_InitStruct.Enable = MPU_REGION_ENABLE;
  MPU_InitStruct.Number = MPU_REGION_NUMBER0;
  MPU_InitStruct.BaseAddress = 0x0;
  MPU_InitStruct.Size = MPU_REGION_SIZE_4GB;
  MPU_InitStruct.SubRegionDisable = 0x87;
  MPU_InitStruct.TypeExtField = MPU_TEX_LEVEL0;
  MPU_InitStruct.AccessPermission = MPU_REGION_NO_ACCESS;
  MPU_InitStruct.DisableExec = MPU_INSTRUCTION_ACCESS_DISABLE;
  MPU_InitStruct.IsShareable = MPU_ACCESS_SHAREABLE;
  MPU_InitStruct.IsCacheable = MPU_ACCESS_NOT_CACHEABLE;
  MPU_InitStruct.IsBufferable = MPU_ACCESS_NOT_BUFFERABLE;

  HAL_MPU_ConfigRegion(&MPU_InitStruct);

  /** Initializes and configures the Region and the memory to be protected
  */
  MPU_InitStruct.Number = MPU_REGION_NUMBER1;
  MPU_InitStruct.BaseAddress = 0x30020000;
  MPU_InitStruct.Size = MPU_REGION_SIZE_128KB;
  MPU_InitStruct.SubRegionDisable = 0x0;
  MPU_InitStruct.TypeExtField = MPU_TEX_LEVEL1;
  MPU_InitStruct.AccessPermission = MPU_REGION_FULL_ACCESS;
  MPU_InitStruct.IsShareable = MPU_ACCESS_NOT_SHAREABLE;

  HAL_MPU_ConfigRegion(&MPU_InitStruct);

  /** Initializes and configures the Region and the memory to be protected
  */
  MPU_InitStruct.Number = MPU_REGION_NUMBER2;
  MPU_InitStruct.BaseAddress = 0x30040000;
  MPU_InitStruct.Size = MPU_REGION_SIZE_512B;
  MPU_InitStruct.TypeExtField = MPU_TEX_LEVEL0;
  MPU_InitStruct.IsShareable = MPU_ACCESS_SHAREABLE;
  MPU_InitStruct.IsBufferable = MPU_ACCESS_BUFFERABLE;

  HAL_MPU_ConfigRegion(&MPU_InitStruct);

  /** Initializes and configures the Region and the memory to be protected
  */
  MPU_InitStruct.Number = MPU_REGION_NUMBER3;
  MPU_InitStruct.BaseAddress = 0xC0000000;
  MPU_InitStruct.Size = MPU_REGION_SIZE_8MB;
  MPU_InitStruct.IsShareable = MPU_ACCESS_NOT_SHAREABLE;
  MPU_InitStruct.IsBufferable = MPU_ACCESS_NOT_BUFFERABLE;

  HAL_MPU_ConfigRegion(&MPU_InitStruct);

  /** Initializes and configures the Region and the memory to be protected
  */
  MPU_InitStruct.Number = MPU_REGION_NUMBER4;
  MPU_InitStruct.BaseAddress = 0x40000000;
  MPU_InitStruct.Size = MPU_REGION_SIZE_512MB;
  MPU_InitStruct.SubRegionDisable = 0x0;
  MPU_InitStruct.TypeExtField = MPU_TEX_LEVEL0;
  MPU_InitStruct.AccessPermission = MPU_REGION_FULL_ACCESS;
  MPU_InitStruct.DisableExec = MPU_INSTRUCTION_ACCESS_DISABLE;
  MPU_InitStruct.IsShareable = MPU_ACCESS_SHAREABLE;
  MPU_InitStruct.IsCacheable = MPU_ACCESS_NOT_CACHEABLE;
  MPU_InitStruct.IsBufferable = MPU_ACCESS_BUFFERABLE;

  HAL_MPU_ConfigRegion(&MPU_InitStruct);

  /* Enables the MPU */
  HAL_MPU_Enable(MPU_PRIVILEGED_DEFAULT);

}

void HAL_TIM_PeriodElapsedCallback(TIM_HandleTypeDef *htim)
{
  if (htim->Instance == TIM1)
  {
    HAL_IncTick();
  }
}

void Error_Handler(void)
{
  __disable_irq();
  while (1)
  {
  }
}
